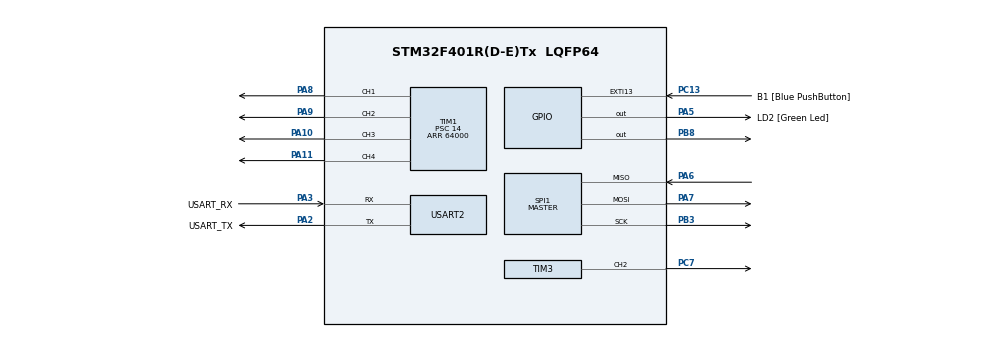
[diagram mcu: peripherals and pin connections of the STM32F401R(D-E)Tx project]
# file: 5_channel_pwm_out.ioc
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Mcu.Family=STM32F4
Mcu.Name=STM32F401R(D-E)Tx
Mcu.Package=LQFP64
NVIC.PriorityGroup=NVIC_PRIORITYGROUP_0
PA10.Signal=S_TIM1_CH3
PA11.Signal=S_TIM1_CH4
PA13.GPIO_Label=TMS
PA13.Mode=Serial_Wire
PA13.Signal=SYS_JTMS-SWDIO
PA14.GPIO_Label=TCK
PA14.Mode=Serial_Wire
PA14.Signal=SYS_JTCK-SWCLK
PA2.GPIO_Label=USART_TX
PA2.GPIO_Mode=GPIO_MODE_AF_PP
PA2.GPIO_PuPd=GPIO_NOPULL
PA2.GPIO_Speed=GPIO_SPEED_FREQ_LOW
PA2.Mode=Asynchronous
PA2.Signal=USART2_TX
PA3.GPIO_Label=USART_RX
PA3.GPIO_Mode=GPIO_MODE_AF_PP
PA3.GPIO_PuPd=GPIO_NOPULL
PA3.GPIO_Speed=GPIO_SPEED_FREQ_LOW
PA3.Mode=Asynchronous
PA3.Signal=USART2_RX
PA5.GPIO_Label=LD2 [Green Led]
PA5.GPIO_Mode=GPIO_MODE_OUTPUT_PP
PA5.GPIO_PuPd=GPIO_NOPULL
PA5.GPIO_Speed=GPIO_SPEED_FREQ_LOW
PA5.Signal=GPIO_Output
PA6.Mode=Full_Duplex_Master
PA6.Signal=SPI1_MISO
PA7.Mode=Full_Duplex_Master
PA7.Signal=SPI1_MOSI
PA8.Signal=S_TIM1_CH1
PA9.Signal=S_TIM1_CH2
PB3.Mode=Full_Duplex_Master
PB3.Signal=SPI1_SCK
PB8.Signal=GPIO_Output
PC13-ANTI_TAMP.GPIO_Label=B1 [Blue PushButton]
PC13-ANTI_TAMP.GPIO_ModeDefaultEXTI=GPIO_MODE_IT_FALLING
PC13-ANTI_TAMP.GPIO_PuPd=GPIO_NOPULL
PC13-ANTI_TAMP.Signal=GPXTI13
PC14-OSC32_IN.Mode=LSE-External-Oscillator
PC14-OSC32_IN.Signal=RCC_OSC32_IN
PC15-OSC32_OUT.Mode=LSE-External-Oscillator
PC15-OSC32_OUT.Signal=RCC_OSC32_OUT
PC7.Signal=S_TIM3_CH2
PH0\ -\ OSC_IN.Mode=HSE-External-Clock-Source
PH0\ -\ OSC_IN.Signal=RCC_OSC_IN
PH1\ -\ OSC_OUT.Mode=HSE-External-Clock-Source
PH1\ -\ OSC_OUT.Signal=RCC_OSC_OUT
ProjectManager.HeapSize=0x200
ProjectManager.StackSize=0x400
ProjectManager.TargetToolchain=STM32CubeIDE
RCC.48MHZClocksFreq_Value=48000000
RCC.AHBFreq_Value=84000000
RCC.APB1CLKDivider=RCC_HCLK_DIV4
RCC.APB1Freq_Value=21000000
RCC.APB1TimFreq_Value=42000000
RCC.APB2CLKDivider=RCC_HCLK_DIV4
RCC.APB2Freq_Value=21000000
RCC.APB2TimFreq_Value=42000000
RCC.CortexFreq_Value=84000000
RCC.HCLKFreq_Value=84000000
RCC.HSE_VALUE=8000000
RCC.HSI_VALUE=16000000
RCC.PLLN=336
RCC.PLLP=RCC_PLLP_DIV4
RCC.PLLQ=7
RCC.SYSCLKFreq_VALUE=84000000
RCC.SYSCLKSource=RCC_SYSCLKSOURCE_PLLCLK
RCC.VCOOutputFreq_Value=336000000
SH.S_TIM1_CH1.0=TIM1_CH1,PWM Generation1 CH1
SH.S_TIM1_CH2.0=TIM1_CH2,PWM Generation2 CH2
SH.S_TIM1_CH3.0=TIM1_CH3,PWM Generation3 CH3
SH.S_TIM1_CH4.0=TIM1_CH4,PWM Generation4 CH4
SH.S_TIM3_CH2.0=TIM3_CH2,PWM Generation2 CH2
SPI1.Direction=SPI_DIRECTION_2LINES
SPI1.Mode=SPI_MODE_MASTER
SPI1.VirtualType=VM_MASTER
TIM1.Channel-PWM\ Generation1\ CH1=TIM_CHANNEL_1
TIM1.Channel-PWM\ Generation2\ CH2=TIM_CHANNEL_2
TIM1.Channel-PWM\ Generation3\ CH3=TIM_CHANNEL_3
TIM1.Channel-PWM\ Generation4\ CH4=TIM_CHANNEL_4
TIM1.Period=64000
TIM1.Prescaler=14
TIM3.Channel-PWM\ Generation2\ CH2=TIM_CHANNEL_2
TIM3.Period=64000
TIM3.Prescaler=14
USART2.VirtualMode=VM_ASYNC
VP_TIM1_VS_ClockSourceINT.Mode=Internal
VP_TIM3_VS_ClockSourceINT.Mode=Internal
board=NUCLEO-F401RE

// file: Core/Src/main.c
/* USER CODE BEGIN Header */
/**
  ******************************************************************************
  * @file           : main.c
  * @brief          : Main program body
  ******************************************************************************
  * @attention
  *
  * Copyright (c) 2022 STMicroelectronics.
  * All rights reserved.
  *
  * This software is licensed under terms that can be found in the LICENSE file
  * in the root directory of this software component.
  * If no LICENSE file comes with this software, it is provided AS-IS.
  *
  ******************************************************************************
  */
/* USER CODE END Header */
#include "main.h"

SPI_HandleTypeDef hspi1;

TIM_HandleTypeDef htim1;
TIM_HandleTypeDef htim3;

UART_HandleTypeDef huart2;

void SystemClock_Config(void);
static void MX_GPIO_Init(void);
static void MX_USART2_UART_Init(void);
static void MX_TIM1_Init(void);
static void MX_TIM3_Init(void);
static void MX_SPI1_Init(void);

int main(void)
{
  /* USER CODE BEGIN 1 */
	const static uint16_t adc_max = 0X03FF;//adc each cycle transmit 10 bit of data
	//3FF represent 00000011 11111111, later used for bit wise operation
	const static uint16_t GPIO_port = 8;

	const static uint16_t CounterPeriod = 64000;//same for both tim1 and tim3
	const static uint16_t DutyCycle_min = 0.05;//the duty cycle for the pwm output is 5%
	const static uint16_t DutyCycle_max = 0.1;

	//config based on the data sheet
	uint8_t data_transmit[3];
	uint8_t data_recieve[3];

	//transmit config data for MCV3004
	data_transmit[0] = 0X01;//00000001
	data_transmit[1] = 0X80;//10000000

	//get the return adc value
	uint16_t ADC_in;
  /* USER CODE END 1 */

  /* MCU Configuration--------------------------------------------------------*/

  /* Reset of all peripherals, Initializes the Flash interface and the Systick. */
  HAL_Init();

  /* Configure the system clock */
  SystemClock_Config();

  /* Initialize all configured peripherals */
  MX_GPIO_Init();
  MX_USART2_UART_Init();
  MX_TIM1_Init();
  MX_TIM3_Init();
  MX_SPI1_Init();
  /* USER CODE BEGIN 2 */
  //pwm timer start
  HAL_TIM_PWM_Start(&htim1, TIM_CHANNEL_1);
  HAL_TIM_PWM_Start(&htim1, TIM_CHANNEL_2);
  HAL_TIM_PWM_Start(&htim1, TIM_CHANNEL_3);
  HAL_TIM_PWM_Start(&htim1, TIM_CHANNEL_4);
  HAL_TIM_PWM_Start(&htim3, TIM_CHANNEL_2);

  //pull up the CS line
  HAL_GPIO_WritePin(GPIOA, GPIO_port , GPIO_PIN_SET);
  /* USER CODE END 2 */

  /* Infinite loop */
  /* USER CODE BEGIN WHILE */
  while (1)
  {

	  double pwm_output = 0.5;//in range 0 to 1
	  pwm_output = (pwm_output * (DutyCycle_max - DutyCycle_min) + DutyCycle_min) * CounterPeriod;//get the value in range from duty cycle max - min and get the amount of counter to compare

	  __HAL_TIM_SET_COMPARE(&htim1, TIM_CHANNEL_1, pwm_output);
	  __HAL_TIM_SET_COMPARE(&htim1, TIM_CHANNEL_2, pwm_output);
	  __HAL_TIM_SET_COMPARE(&htim1, TIM_CHANNEL_3, pwm_output);
	  __HAL_TIM_SET_COMPARE(&htim1, TIM_CHANNEL_4, pwm_output);
	  __HAL_TIM_SET_COMPARE(&htim3, TIM_CHANNEL_2, pwm_output);

    /* USER CODE END WHILE */

    /* USER CODE BEGIN 3 */
	 c
  }
  /* USER CODE END 3 */
}

void SystemClock_Config(void)
{
  RCC_OscInitTypeDef RCC_OscInitStruct = {0};
  RCC_ClkInitTypeDef RCC_ClkInitStruct = {0};

  /** Configure the main internal regulator output voltage
  */
  __HAL_RCC_PWR_CLK_ENABLE();
  __HAL_PWR_VOLTAGESCALING_CONFIG(PWR_REGULATOR_VOLTAGE_SCALE2);

  /** Initializes the RCC Oscillators according to the specified parameters
  * in the RCC_OscInitTypeDef structure.
  */
  RCC_OscInitStruct.OscillatorType = RCC_OSCILLATORTYPE_HSI;
  RCC_OscInitStruct.HSIState = RCC_HSI_ON;
  RCC_OscInitStruct.HSICalibrationValue = RCC_HSICALIBRATION_DEFAULT;
  RCC_OscInitStruct.PLL.PLLState = RCC_PLL_ON;
  RCC_OscInitStruct.PLL.PLLSource = RCC_PLLSOURCE_HSI;
  RCC_OscInitStruct.PLL.PLLM = 8;
  RCC_OscInitStruct.PLL.PLLN = 96;
  RCC_OscInitStruct.PLL.PLLP = RCC_PLLP_DIV4;
  RCC_OscInitStruct.PLL.PLLQ = 7;
  if (HAL_RCC_OscConfig(&RCC_OscInitStruct) != HAL_OK)
  {
    Error_Handler();
  }

  /** Initializes the CPU, AHB and APB buses clocks
  */
  RCC_ClkInitStruct.ClockType = RCC_CLOCKTYPE_HCLK|RCC_CLOCKTYPE_SYSCLK
                              |RCC_CLOCKTYPE_PCLK1|RCC_CLOCKTYPE_PCLK2;
  RCC_ClkInitStruct.SYSCLKSource = RCC_SYSCLKSOURCE_PLLCLK;
  RCC_ClkInitStruct.AHBCLKDivider = RCC_SYSCLK_DIV1;
  RCC_ClkInitStruct.APB1CLKDivider = RCC_HCLK_DIV2;
  RCC_ClkInitStruct.APB2CLKDivider = RCC_HCLK_DIV4;

  if (HAL_RCC_ClockConfig(&RCC_ClkInitStruct, FLASH_LATENCY_1) != HAL_OK)
  {
    Error_Handler();
  }
}

static void MX_SPI1_Init(void)
{

  /* SPI1 parameter configuration*/
  hspi1.Instance = SPI1;
  hspi1.Init.Mode = SPI_MODE_MASTER;
  hspi1.Init.Direction = SPI_DIRECTION_2LINES;
  hspi1.Init.DataSize = SPI_DATASIZE_8BIT;
  hspi1.Init.CLKPolarity = SPI_POLARITY_LOW;
  hspi1.Init.CLKPhase = SPI_PHASE_1EDGE;
  hspi1.Init.NSS = SPI_NSS_SOFT;
  hspi1.Init.BaudRatePrescaler = SPI_BAUDRATEPRESCALER_2;
  hspi1.Init.FirstBit = SPI_FIRSTBIT_MSB;
  hspi1.Init.TIMode = SPI_TIMODE_DISABLE;
  hspi1.Init.CRCCalculation = SPI_CRCCALCULATION_DISABLE;
  hspi1.Init.CRCPolynomial = 10;
  if (HAL_SPI_Init(&hspi1) != HAL_OK)
  {
    Error_Handler();
  }

}

static void MX_TIM1_Init(void)
{

  TIM_ClockConfigTypeDef sClockSourceConfig = {0};
  TIM_MasterConfigTypeDef sMasterConfig = {0};
  TIM_OC_InitTypeDef sConfigOC = {0};
  TIM_BreakDeadTimeConfigTypeDef sBreakDeadTimeConfig = {0};

  htim1.Instance = TIM1;
  htim1.Init.Prescaler = 14;
  htim1.Init.CounterMode = TIM_COUNTERMODE_UP;
  htim1.Init.Period = 64000;
  htim1.Init.ClockDivision = TIM_CLOCKDIVISION_DIV1;
  htim1.Init.RepetitionCounter = 0;
  htim1.Init.AutoReloadPreload = TIM_AUTORELOAD_PRELOAD_DISABLE;
  if (HAL_TIM_Base_Init(&htim1) != HAL_OK)
  {
    Error_Handler();
  }
  sClockSourceConfig.ClockSource = TIM_CLOCKSOURCE_INTERNAL;
  if (HAL_TIM_ConfigClockSource(&htim1, &sClockSourceConfig) != HAL_OK)
  {
    Error_Handler();
  }
  if (HAL_TIM_PWM_Init(&htim1) != HAL_OK)
  {
    Error_Handler();
  }
  sMasterConfig.MasterOutputTrigger = TIM_TRGO_RESET;
  sMasterConfig.MasterSlaveMode = TIM_MASTERSLAVEMODE_DISABLE;
  if (HAL_TIMEx_MasterConfigSynchronization(&htim1, &sMasterConfig) != HAL_OK)
  {
    Error_Handler();
  }
  sConfigOC.OCMode = TIM_OCMODE_PWM1;
  sConfigOC.Pulse = 0;
  sConfigOC.OCPolarity = TIM_OCPOLARITY_HIGH;
  sConfigOC.OCNPolarity = TIM_OCNPOLARITY_HIGH;
  sConfigOC.OCFastMode = TIM_OCFAST_DISABLE;
  sConfigOC.OCIdleState = TIM_OCIDLESTATE_RESET;
  sConfigOC.OCNIdleState = TIM_OCNIDLESTATE_RESET;
  if (HAL_TIM_PWM_ConfigChannel(&htim1, &sConfigOC, TIM_CHANNEL_1) != HAL_OK)
  {
    Error_Handler();
  }
  if (HAL_TIM_PWM_ConfigChannel(&htim1, &sConfigOC, TIM_CHANNEL_2) != HAL_OK)
  {
    Error_Handler();
  }
  if (HAL_TIM_PWM_ConfigChannel(&htim1, &sConfigOC, TIM_CHANNEL_3) != HAL_OK)
  {
    Error_Handler();
  }
  if (HAL_TIM_PWM_ConfigChannel(&htim1, &sConfigOC, TIM_CHANNEL_4) != HAL_OK)
  {
    Error_Handler();
  }
  sBreakDeadTimeConfig.OffStateRunMode = TIM_OSSR_DISABLE;
  sBreakDeadTimeConfig.OffStateIDLEMode = TIM_OSSI_DISABLE;
  sBreakDeadTimeConfig.LockLevel = TIM_LOCKLEVEL_OFF;
  sBreakDeadTimeConfig.DeadTime = 0;
  sBreakDeadTimeConfig.BreakState = TIM_BREAK_DISABLE;
  sBreakDeadTimeConfig.BreakPolarity = TIM_BREAKPOLARITY_HIGH;
  sBreakDeadTimeConfig.AutomaticOutput = TIM_AUTOMATICOUTPUT_DISABLE;
  if (HAL_TIMEx_ConfigBreakDeadTime(&htim1, &sBreakDeadTimeConfig) != HAL_OK)
  {
    Error_Handler();
  }
  HAL_TIM_MspPostInit(&htim1);

}

static void MX_TIM3_Init(void)
{

  TIM_ClockConfigTypeDef sClockSourceConfig = {0};
  TIM_MasterConfigTypeDef sMasterConfig = {0};
  TIM_OC_InitTypeDef sConfigOC = {0};

  htim3.Instance = TIM3;
  htim3.Init.Prescaler = 14;
  htim3.Init.CounterMode = TIM_COUNTERMODE_UP;
  htim3.Init.Period = 64000;
  htim3.Init.ClockDivision = TIM_CLOCKDIVISION_DIV1;
  htim3.Init.AutoReloadPreload = TIM_AUTORELOAD_PRELOAD_DISABLE;
  if (HAL_TIM_Base_Init(&htim3) != HAL_OK)
  {
    Error_Handler();
  }
  sClockSourceConfig.ClockSource = TIM_CLOCKSOURCE_INTERNAL;
  if (HAL_TIM_ConfigClockSource(&htim3, &sClockSourceConfig) != HAL_OK)
  {
    Error_Handler();
  }
  if (HAL_TIM_PWM_Init(&htim3) != HAL_OK)
  {
    Error_Handler();
  }
  sMasterConfig.MasterOutputTrigger = TIM_TRGO_RESET;
  sMasterConfig.MasterSlaveMode = TIM_MASTERSLAVEMODE_DISABLE;
  if (HAL_TIMEx_MasterConfigSynchronization(&htim3, &sMasterConfig) != HAL_OK)
  {
    Error_Handler();
  }
  sConfigOC.OCMode = TIM_OCMODE_PWM1;
  sConfigOC.Pulse = 0;
  sConfigOC.OCPolarity = TIM_OCPOLARITY_HIGH;
  sConfigOC.OCFastMode = TIM_OCFAST_DISABLE;
  if (HAL_TIM_PWM_ConfigChannel(&htim3, &sConfigOC, TIM_CHANNEL_2) != HAL_OK)
  {
    Error_Handler();
  }
  HAL_TIM_MspPostInit(&htim3);

}

static void MX_USART2_UART_Init(void)
{

  huart2.Instance = USART2;
  huart2.Init.BaudRate = 115200;
  huart2.Init.WordLength = UART_WORDLENGTH_8B;
  huart2.Init.StopBits = UART_STOPBITS_1;
  huart2.Init.Parity = UART_PARITY_NONE;
  huart2.Init.Mode = UART_MODE_TX_RX;
  huart2.Init.HwFlowCtl = UART_HWCONTROL_NONE;
  huart2.Init.OverSampling = UART_OVERSAMPLING_16;
  if (HAL_UART_Init(&huart2) != HAL_OK)
  {
    Error_Handler();
  }

}

static void MX_GPIO_Init(void)
{
  GPIO_InitTypeDef GPIO_InitStruct = {0};

  /* GPIO Ports Clock Enable */
  __HAL_RCC_GPIOC_CLK_ENABLE();
  __HAL_RCC_GPIOH_CLK_ENABLE();
  __HAL_RCC_GPIOA_CLK_ENABLE();
  __HAL_RCC_GPIOB_CLK_ENABLE();

  /*Configure GPIO pin Output Level */
  HAL_GPIO_WritePin(LD2_GPIO_Port, LD2_Pin, GPIO_PIN_RESET);

  /*Configure GPIO pin Output Level */
  HAL_GPIO_WritePin(GPIOB, GPIO_PIN_8, GPIO_PIN_RESET);

  /*Configure GPIO pin : B1_Pin */
  GPIO_InitStruct.Pin = B1_Pin;
  GPIO_InitStruct.Mode = GPIO_MODE_IT_FALLING;
  GPIO_InitStruct.Pull = GPIO_NOPULL;
  HAL_GPIO_Init(B1_GPIO_Port, &GPIO_InitStruct);

  /*Configure GPIO pin : LD2_Pin */
  GPIO_InitStruct.Pin = LD2_Pin;
  GPIO_InitStruct.Mode = GPIO_MODE_OUTPUT_PP;
  GPIO_InitStruct.Pull = GPIO_NOPULL;
  GPIO_InitStruct.Speed = GPIO_SPEED_FREQ_LOW;
  HAL_GPIO_Init(LD2_GPIO_Port, &GPIO_InitStruct);

  /*Configure GPIO pin : PB8 */
  GPIO_InitStruct.Pin = GPIO_PIN_8;
  GPIO_InitStruct.Mode = GPIO_MODE_OUTPUT_PP;
  GPIO_InitStruct.Pull = GPIO_NOPULL;
  GPIO_InitStruct.Speed = GPIO_SPEED_FREQ_LOW;
  HAL_GPIO_Init(GPIOB, &GPIO_InitStruct);

}

void Error_Handler(void)
{
  __disable_irq();
  while (1)
  {
  }
}
